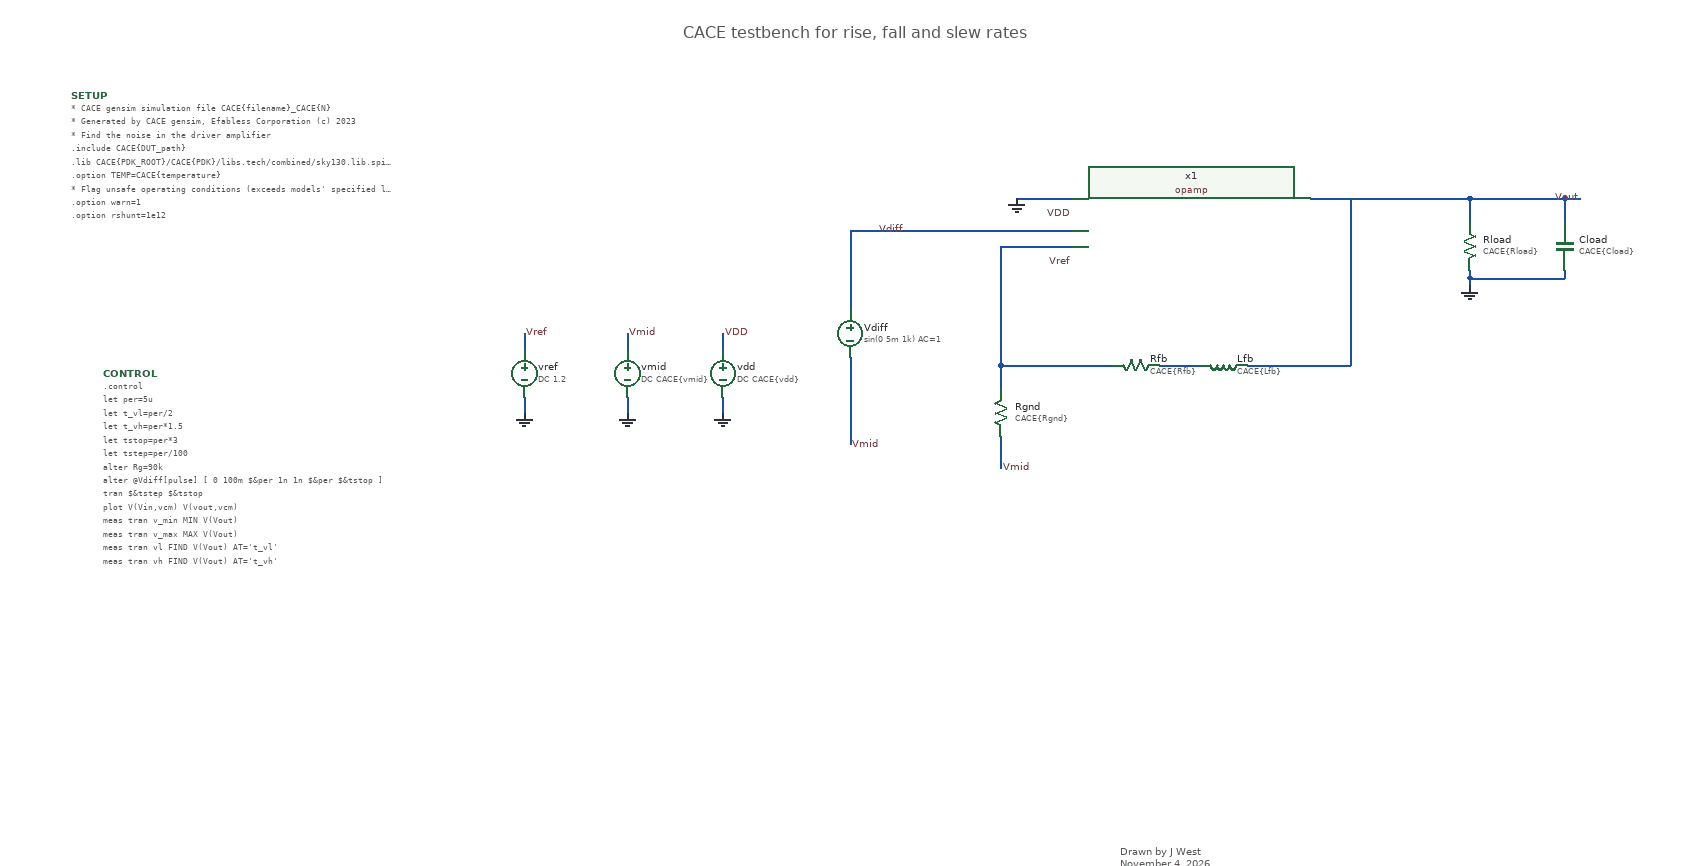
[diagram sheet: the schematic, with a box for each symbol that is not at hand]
v {xschem version=3.4.8RC file_version=1.3}
G {}
K {}
V {}
S {}
F {}
E {}
T {CACE testbench for rise, fall and slew rates} -390 -640 0 0 0.6 0.6 {}
T {Drawn by J West
November 4, 2026
Revision 0
} 160 390 0 0 0.4 0.4 {}
N 720 -420 740 -420 {
lab=Vout}
N -340 -170 -340 -150 {lab=GND}
N -340 -250 -340 -230 {lab=VDD}
N 10 -120 10 -110 {lab=Vmid}
N 600 -320 600 -310 {lab=GND}
N 600 -330 600 -320 {lab=GND}
N 650 -320 720 -320 {lab=GND}
N 720 -330 720 -320 {lab=GND}
N 720 -420 720 -390 {lab=Vout}
N 600 -420 600 -390 {lab=Vout}
N -180 -320 -180 -280 {lab=Vdiff}
N -180 -220 -180 -180 {lab=Vmid}
N -180 -180 -180 -140 {lab=Vmid}
N 650 -420 720 -420 {
lab=Vout}
N 400 -420 600 -420 {
lab=Vout}
N 600 -420 650 -420 {lab=Vout}
N 600 -320 650 -320 {lab=GND}
N 10 -110 10 -80 {lab=Vmid}
N -460 -170 -460 -150 {lab=GND}
N -460 -250 -460 -230 {lab=Vmid}
N 30 -420 100 -420 {lab=GND}
N -180 -380 -180 -320 {lab=Vdiff}
N -180 -380 100 -380 {lab=Vdiff}
N 10 -360 100 -360 {lab=#net1}
N 10 -360 10 -210 {lab=#net1}
N 10 -210 150 -210 {lab=#net1}
N 10 -210 10 -180 {lab=#net1}
N 210 -210 260 -210 {lab=#net2}
N 320 -210 450 -210 {lab=Vout}
N 450 -420 450 -210 {lab=Vout}
N -180 -140 -180 -110 {lab=Vmid}
N -590 -170 -590 -150 {lab=GND}
N -590 -250 -590 -230 {lab=Vmid}
C {devices/code_shown.sym} -1120 -200 0 0 {name=CONTROL only_toplevel=false value=".control
let per=5u
let t_vl=per/2
let t_vh=per*1.5
let tstop=per*3
let tstep=per/100
alter Rg=90k
alter @Vdiff[pulse] [ 0 100m $&per 1n 1n $&per $&tstop ] 
tran $&tstep $&tstop
plot V(Vin,vcm) V(vout,vcm)
meas tran v_min MIN V(Vout)
meas tran v_max MAX V(Vout)
meas tran vl FIND V(Vout) AT='t_vl'
meas tran vh FIND V(Vout) AT='t_vh'
meas tran v_pp PP V(Vout)
let v_high=(0.9*v_pp)+v_min
let v_low=(0.1*v_pp)+v_min
meas tran rise_time TRIG v(Vout) VAL='v_low' rise=1 targ v(vout) Val='v_high' RISE=1
meas tran fall_time TRIG v(Vout) VAL='v_high' fall=1 targ v(vout) Val='v_low' FALL=1
let sr_rise=(v_high-v_low)/rise_time
let sr_fall=(v_high-v_low)/fall_time
let over=v_max-vh
let under=vl-v_min
let sup_current = -i(Vdd)
meas tran ivdd AVG sup_current from=0 to='per' 

set gnuplot_terminal=png/quit
gnuplot v_rise_fall V(vin,vcm) V(Vout,vcm)
+ title 'Rise and Fall Times'
+ xlabel 'Time (s)' ylabel 'Volts'

echo $&rise_time $&fall_time $&sr_rise $&sr_fall $&over $&under $&ivdd> CACE\{simpath\}/CACE\{filename\}_CACE\{N\}.data

quit
.endc
"}
C {devices/code_shown.sym} -1160 -550 0 0 {name=SETUP only_toplevel=false value="* CACE gensim simulation file CACE\{filename\}_CACE\{N\}
* Generated by CACE gensim, Efabless Corporation (c) 2023
* Find the noise in the driver amplifier

.include CACE\{DUT_path\}

.lib CACE\{PDK_ROOT\}/CACE\{PDK\}/libs.tech/combined/sky130.lib.spice CACE\{corner\}

.option TEMP=CACE\{temperature\}
* Flag unsafe operating conditions (exceeds models' specified limits)
.option warn=1
.option rshunt=1e12
"}
C {devices/lab_wire.sym} 740 -420 0 0 {name=p25 sig_type=std_logic lab=Vout}
C {devices/vsource.sym} -340 -200 0 0 {name=vdd value="DC CACE\{vdd\}" savecurrent=false}
C {devices/gnd.sym} -340 -150 0 0 {name=l1 lab=GND}
C {devices/res.sym} 600 -360 0 0 {name=Rload
value=CACE\{Rload\}
device=resistor}
C {capa.sym} 720 -360 0 0 {name=Cload
m=1
value=CACE\{Cload\}
footprint=1206
device="ceramic capacitor"}
C {devices/gnd.sym} 600 -310 0 0 {name=l3 lab=GND}
C {vsource.sym} -180 -250 0 0 {name=Vdiff value="sin(0 5m 1k) AC=1"}
C {devices/lab_wire.sym} 10 -80 0 1 {name=p2 sig_type=std_logic lab=Vmid}
C {opamp.sym} 250 -380 0 0 {name=x1}
C {devices/vsource.sym} -460 -200 0 0 {name=vmid value="DC CACE\{vmid\}" savecurrent=false}
C {devices/gnd.sym} -460 -150 0 0 {name=vmid1 lab=GND
value="DC CACE\{vmid\}"}
C {devices/lab_wire.sym} -460 -250 0 1 {name=p7 sig_type=std_logic lab=Vmid}
C {devices/lab_wire.sym} -340 -250 0 1 {name=p1 sig_type=std_logic lab=VDD}
C {devices/gnd.sym} 30 -420 1 0 {name=l2 lab=GND}
C {devices/lab_wire.sym} 100 -400 0 0 {name=p3 sig_type=std_logic lab=VDD}
C {res.sym} 180 -210 1 0 {name=Rfb
value=CACE\{Rfb\}
footprint=1206
device=resistor
m=1}
C {res.sym} 10 -150 2 0 {name=Rgnd
value=CACE\{Rgnd\}
footprint=1206
device=resistor
m=1}
C {ind.sym} 290 -210 1 0 {name=Lfb
m=1
value=CACE\{Lfb\}
footprint=1206
device=inductor}
C {devices/lab_wire.sym} -180 -110 0 1 {name=p4 sig_type=std_logic lab=Vmid}
C {devices/lab_wire.sym} -110 -380 0 0 {name=p5 sig_type=std_logic lab=Vdiff}
C {devices/vsource.sym} -590 -200 0 0 {name=vref value="DC 1.2" savecurrent=false}
C {devices/gnd.sym} -590 -150 0 0 {name=vref1 lab=GND
value="DC CACE\{vmid\}"}
C {devices/lab_wire.sym} -590 -250 0 1 {name=vref2 sig_type=std_logic lab=Vref
}
C {devices/lab_wire.sym} 100 -340 0 0 {name=p6 sig_type=std_logic lab=Vref}
